# Generated deterministically by seda-macro-lef-normalizer-v1; recipe orfs-ng45-fakeram-metal3-coupledl2-pg-v1.
VERSION 5.8 ;
BUSBITCHARS "[]" ;
DIVIDERCHAR "/" ;

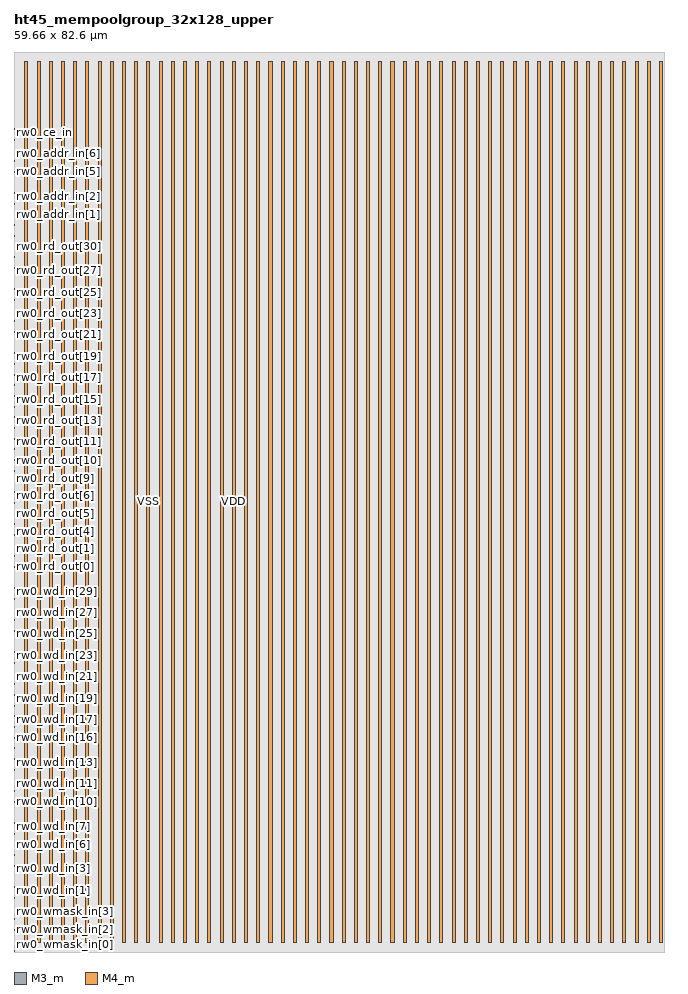
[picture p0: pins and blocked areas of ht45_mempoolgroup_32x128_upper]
MACRO ht45_mempoolgroup_32x128_upper
  FOREIGN ht45_mempoolgroup_32x128_upper 0 0 ;
  CLASS COVER ;
  ORIGIN 0 0 ;
  SIZE 59.66 BY 82.6 ;
  SYMMETRY X Y R90 ;
  PIN rw0_wmask_in[0]
    DIRECTION INPUT ;
    USE SIGNAL ;
    SHAPE ABUTMENT ;
    PORT
      LAYER M3_m ;
      RECT 0 0.035 0.07 0.105 ;
    END
  END rw0_wmask_in[0]
  PIN rw0_wmask_in[1]
    DIRECTION INPUT ;
    USE SIGNAL ;
    SHAPE ABUTMENT ;
    PORT
      LAYER M3_m ;
      RECT 0 1.015 0.07 1.085 ;
    END
  END rw0_wmask_in[1]
  PIN rw0_wmask_in[2]
    DIRECTION INPUT ;
    USE SIGNAL ;
    SHAPE ABUTMENT ;
    PORT
      LAYER M3_m ;
      RECT 0 1.995 0.07 2.065 ;
    END
  END rw0_wmask_in[2]
  PIN rw0_wmask_in[3]
    DIRECTION INPUT ;
    USE SIGNAL ;
    SHAPE ABUTMENT ;
    PORT
      LAYER M3_m ;
      RECT 0 2.975 0.07 3.045 ;
    END
  END rw0_wmask_in[3]
  PIN rw0_wd_in[0]
    DIRECTION INPUT ;
    USE SIGNAL ;
    SHAPE ABUTMENT ;
    PORT
      LAYER M3_m ;
      RECT 0 3.955 0.07 4.025 ;
    END
  END rw0_wd_in[0]
  PIN rw0_wd_in[1]
    DIRECTION INPUT ;
    USE SIGNAL ;
    SHAPE ABUTMENT ;
    PORT
      LAYER M3_m ;
      RECT 0 4.935 0.07 5.005 ;
    END
  END rw0_wd_in[1]
  PIN rw0_wd_in[2]
    DIRECTION INPUT ;
    USE SIGNAL ;
    SHAPE ABUTMENT ;
    PORT
      LAYER M3_m ;
      RECT 0 5.915 0.07 5.985 ;
    END
  END rw0_wd_in[2]
  PIN rw0_wd_in[3]
    DIRECTION INPUT ;
    USE SIGNAL ;
    SHAPE ABUTMENT ;
    PORT
      LAYER M3_m ;
      RECT 0 6.895 0.07 6.965 ;
    END
  END rw0_wd_in[3]
  PIN rw0_wd_in[4]
    DIRECTION INPUT ;
    USE SIGNAL ;
    SHAPE ABUTMENT ;
    PORT
      LAYER M3_m ;
      RECT 0 7.875 0.07 7.945 ;
    END
  END rw0_wd_in[4]
  PIN rw0_wd_in[5]
    DIRECTION INPUT ;
    USE SIGNAL ;
    SHAPE ABUTMENT ;
    PORT
      LAYER M3_m ;
      RECT 0 8.855 0.07 8.925 ;
    END
  END rw0_wd_in[5]
  PIN rw0_wd_in[6]
    DIRECTION INPUT ;
    USE SIGNAL ;
    SHAPE ABUTMENT ;
    PORT
      LAYER M3_m ;
      RECT 0 9.835 0.07 9.905 ;
    END
  END rw0_wd_in[6]
  PIN rw0_wd_in[7]
    DIRECTION INPUT ;
    USE SIGNAL ;
    SHAPE ABUTMENT ;
    PORT
      LAYER M3_m ;
      RECT 0 10.815 0.07 10.885 ;
    END
  END rw0_wd_in[7]
  PIN rw0_wd_in[8]
    DIRECTION INPUT ;
    USE SIGNAL ;
    SHAPE ABUTMENT ;
    PORT
      LAYER M3_m ;
      RECT 0 11.795 0.07 11.865 ;
    END
  END rw0_wd_in[8]
  PIN rw0_wd_in[9]
    DIRECTION INPUT ;
    USE SIGNAL ;
    SHAPE ABUTMENT ;
    PORT
      LAYER M3_m ;
      RECT 0 12.775 0.07 12.845 ;
    END
  END rw0_wd_in[9]
  PIN rw0_wd_in[10]
    DIRECTION INPUT ;
    USE SIGNAL ;
    SHAPE ABUTMENT ;
    PORT
      LAYER M3_m ;
      RECT 0 13.755 0.07 13.825 ;
    END
  END rw0_wd_in[10]
  PIN rw0_wd_in[11]
    DIRECTION INPUT ;
    USE SIGNAL ;
    SHAPE ABUTMENT ;
    PORT
      LAYER M3_m ;
      RECT 0 14.735 0.07 14.805 ;
    END
  END rw0_wd_in[11]
  PIN rw0_wd_in[12]
    DIRECTION INPUT ;
    USE SIGNAL ;
    SHAPE ABUTMENT ;
    PORT
      LAYER M3_m ;
      RECT 0 15.715 0.07 15.785 ;
    END
  END rw0_wd_in[12]
  PIN rw0_wd_in[13]
    DIRECTION INPUT ;
    USE SIGNAL ;
    SHAPE ABUTMENT ;
    PORT
      LAYER M3_m ;
      RECT 0 16.695 0.07 16.765 ;
    END
  END rw0_wd_in[13]
  PIN rw0_wd_in[14]
    DIRECTION INPUT ;
    USE SIGNAL ;
    SHAPE ABUTMENT ;
    PORT
      LAYER M3_m ;
      RECT 0 17.675 0.07 17.745 ;
    END
  END rw0_wd_in[14]
  PIN rw0_wd_in[15]
    DIRECTION INPUT ;
    USE SIGNAL ;
    SHAPE ABUTMENT ;
    PORT
      LAYER M3_m ;
      RECT 0 18.655 0.07 18.725 ;
    END
  END rw0_wd_in[15]
  PIN rw0_wd_in[16]
    DIRECTION INPUT ;
    USE SIGNAL ;
    SHAPE ABUTMENT ;
    PORT
      LAYER M3_m ;
      RECT 0 19.635 0.07 19.705 ;
    END
  END rw0_wd_in[16]
  PIN rw0_wd_in[17]
    DIRECTION INPUT ;
    USE SIGNAL ;
    SHAPE ABUTMENT ;
    PORT
      LAYER M3_m ;
      RECT 0 20.615 0.07 20.685 ;
    END
  END rw0_wd_in[17]
  PIN rw0_wd_in[18]
    DIRECTION INPUT ;
    USE SIGNAL ;
    SHAPE ABUTMENT ;
    PORT
      LAYER M3_m ;
      RECT 0 21.595 0.07 21.665 ;
    END
  END rw0_wd_in[18]
  PIN rw0_wd_in[19]
    DIRECTION INPUT ;
    USE SIGNAL ;
    SHAPE ABUTMENT ;
    PORT
      LAYER M3_m ;
      RECT 0 22.575 0.07 22.645 ;
    END
  END rw0_wd_in[19]
  PIN rw0_wd_in[20]
    DIRECTION INPUT ;
    USE SIGNAL ;
    SHAPE ABUTMENT ;
    PORT
      LAYER M3_m ;
      RECT 0 23.555 0.07 23.625 ;
    END
  END rw0_wd_in[20]
  PIN rw0_wd_in[21]
    DIRECTION INPUT ;
    USE SIGNAL ;
    SHAPE ABUTMENT ;
    PORT
      LAYER M3_m ;
      RECT 0 24.535 0.07 24.605 ;
    END
  END rw0_wd_in[21]
  PIN rw0_wd_in[22]
    DIRECTION INPUT ;
    USE SIGNAL ;
    SHAPE ABUTMENT ;
    PORT
      LAYER M3_m ;
      RECT 0 25.515 0.07 25.585 ;
    END
  END rw0_wd_in[22]
  PIN rw0_wd_in[23]
    DIRECTION INPUT ;
    USE SIGNAL ;
    SHAPE ABUTMENT ;
    PORT
      LAYER M3_m ;
      RECT 0 26.495 0.07 26.565 ;
    END
  END rw0_wd_in[23]
  PIN rw0_wd_in[24]
    DIRECTION INPUT ;
    USE SIGNAL ;
    SHAPE ABUTMENT ;
    PORT
      LAYER M3_m ;
      RECT 0 27.475 0.07 27.545 ;
    END
  END rw0_wd_in[24]
  PIN rw0_wd_in[25]
    DIRECTION INPUT ;
    USE SIGNAL ;
    SHAPE ABUTMENT ;
    PORT
      LAYER M3_m ;
      RECT 0 28.455 0.07 28.525 ;
    END
  END rw0_wd_in[25]
  PIN rw0_wd_in[26]
    DIRECTION INPUT ;
    USE SIGNAL ;
    SHAPE ABUTMENT ;
    PORT
      LAYER M3_m ;
      RECT 0 29.435 0.07 29.505 ;
    END
  END rw0_wd_in[26]
  PIN rw0_wd_in[27]
    DIRECTION INPUT ;
    USE SIGNAL ;
    SHAPE ABUTMENT ;
    PORT
      LAYER M3_m ;
      RECT 0 30.415 0.07 30.485 ;
    END
  END rw0_wd_in[27]
  PIN rw0_wd_in[28]
    DIRECTION INPUT ;
    USE SIGNAL ;
    SHAPE ABUTMENT ;
    PORT
      LAYER M3_m ;
      RECT 0 31.395 0.07 31.465 ;
    END
  END rw0_wd_in[28]
  PIN rw0_wd_in[29]
    DIRECTION INPUT ;
    USE SIGNAL ;
    SHAPE ABUTMENT ;
    PORT
      LAYER M3_m ;
      RECT 0 32.375 0.07 32.445 ;
    END
  END rw0_wd_in[29]
  PIN rw0_wd_in[30]
    DIRECTION INPUT ;
    USE SIGNAL ;
    SHAPE ABUTMENT ;
    PORT
      LAYER M3_m ;
      RECT 0 33.355 0.07 33.425 ;
    END
  END rw0_wd_in[30]
  PIN rw0_wd_in[31]
    DIRECTION INPUT ;
    USE SIGNAL ;
    SHAPE ABUTMENT ;
    PORT
      LAYER M3_m ;
      RECT 0 34.335 0.07 34.405 ;
    END
  END rw0_wd_in[31]
  PIN rw0_rd_out[0]
    DIRECTION OUTPUT ;
    USE SIGNAL ;
    SHAPE ABUTMENT ;
    PORT
      LAYER M3_m ;
      RECT 0 35.315 0.07 35.385 ;
    END
  END rw0_rd_out[0]
  PIN rw0_rd_out[1]
    DIRECTION OUTPUT ;
    USE SIGNAL ;
    SHAPE ABUTMENT ;
    PORT
      LAYER M3_m ;
      RECT 0 36.295 0.07 36.365 ;
    END
  END rw0_rd_out[1]
  PIN rw0_rd_out[2]
    DIRECTION OUTPUT ;
    USE SIGNAL ;
    SHAPE ABUTMENT ;
    PORT
      LAYER M3_m ;
      RECT 0 37.275 0.07 37.345 ;
    END
  END rw0_rd_out[2]
  PIN rw0_rd_out[3]
    DIRECTION OUTPUT ;
    USE SIGNAL ;
    SHAPE ABUTMENT ;
    PORT
      LAYER M3_m ;
      RECT 0 38.255 0.07 38.325 ;
    END
  END rw0_rd_out[3]
  PIN rw0_rd_out[4]
    DIRECTION OUTPUT ;
    USE SIGNAL ;
    SHAPE ABUTMENT ;
    PORT
      LAYER M3_m ;
      RECT 0 39.235 0.07 39.305 ;
    END
  END rw0_rd_out[4]
  PIN rw0_rd_out[5]
    DIRECTION OUTPUT ;
    USE SIGNAL ;
    SHAPE ABUTMENT ;
    PORT
      LAYER M3_m ;
      RECT 0 40.215 0.07 40.285 ;
    END
  END rw0_rd_out[5]
  PIN rw0_rd_out[6]
    DIRECTION OUTPUT ;
    USE SIGNAL ;
    SHAPE ABUTMENT ;
    PORT
      LAYER M3_m ;
      RECT 0 41.195 0.07 41.265 ;
    END
  END rw0_rd_out[6]
  PIN rw0_rd_out[7]
    DIRECTION OUTPUT ;
    USE SIGNAL ;
    SHAPE ABUTMENT ;
    PORT
      LAYER M3_m ;
      RECT 0 42.175 0.07 42.245 ;
    END
  END rw0_rd_out[7]
  PIN rw0_rd_out[8]
    DIRECTION OUTPUT ;
    USE SIGNAL ;
    SHAPE ABUTMENT ;
    PORT
      LAYER M3_m ;
      RECT 0 43.155 0.07 43.225 ;
    END
  END rw0_rd_out[8]
  PIN rw0_rd_out[9]
    DIRECTION OUTPUT ;
    USE SIGNAL ;
    SHAPE ABUTMENT ;
    PORT
      LAYER M3_m ;
      RECT 0 44.135 0.07 44.205 ;
    END
  END rw0_rd_out[9]
  PIN rw0_rd_out[10]
    DIRECTION OUTPUT ;
    USE SIGNAL ;
    SHAPE ABUTMENT ;
    PORT
      LAYER M3_m ;
      RECT 0 45.115 0.07 45.185 ;
    END
  END rw0_rd_out[10]
  PIN rw0_rd_out[11]
    DIRECTION OUTPUT ;
    USE SIGNAL ;
    SHAPE ABUTMENT ;
    PORT
      LAYER M3_m ;
      RECT 0 46.095 0.07 46.165 ;
    END
  END rw0_rd_out[11]
  PIN rw0_rd_out[12]
    DIRECTION OUTPUT ;
    USE SIGNAL ;
    SHAPE ABUTMENT ;
    PORT
      LAYER M3_m ;
      RECT 0 47.075 0.07 47.145 ;
    END
  END rw0_rd_out[12]
  PIN rw0_rd_out[13]
    DIRECTION OUTPUT ;
    USE SIGNAL ;
    SHAPE ABUTMENT ;
    PORT
      LAYER M3_m ;
      RECT 0 48.055 0.07 48.125 ;
    END
  END rw0_rd_out[13]
  PIN rw0_rd_out[14]
    DIRECTION OUTPUT ;
    USE SIGNAL ;
    SHAPE ABUTMENT ;
    PORT
      LAYER M3_m ;
      RECT 0 49.035 0.07 49.105 ;
    END
  END rw0_rd_out[14]
  PIN rw0_rd_out[15]
    DIRECTION OUTPUT ;
    USE SIGNAL ;
    SHAPE ABUTMENT ;
    PORT
      LAYER M3_m ;
      RECT 0 50.015 0.07 50.085 ;
    END
  END rw0_rd_out[15]
  PIN rw0_rd_out[16]
    DIRECTION OUTPUT ;
    USE SIGNAL ;
    SHAPE ABUTMENT ;
    PORT
      LAYER M3_m ;
      RECT 0 50.995 0.07 51.065 ;
    END
  END rw0_rd_out[16]
  PIN rw0_rd_out[17]
    DIRECTION OUTPUT ;
    USE SIGNAL ;
    SHAPE ABUTMENT ;
    PORT
      LAYER M3_m ;
      RECT 0 51.975 0.07 52.045 ;
    END
  END rw0_rd_out[17]
  PIN rw0_rd_out[18]
    DIRECTION OUTPUT ;
    USE SIGNAL ;
    SHAPE ABUTMENT ;
    PORT
      LAYER M3_m ;
      RECT 0 52.955 0.07 53.025 ;
    END
  END rw0_rd_out[18]
  PIN rw0_rd_out[19]
    DIRECTION OUTPUT ;
    USE SIGNAL ;
    SHAPE ABUTMENT ;
    PORT
      LAYER M3_m ;
      RECT 0 53.935 0.07 54.005 ;
    END
  END rw0_rd_out[19]
  PIN rw0_rd_out[20]
    DIRECTION OUTPUT ;
    USE SIGNAL ;
    SHAPE ABUTMENT ;
    PORT
      LAYER M3_m ;
      RECT 0 54.915 0.07 54.985 ;
    END
  END rw0_rd_out[20]
  PIN rw0_rd_out[21]
    DIRECTION OUTPUT ;
    USE SIGNAL ;
    SHAPE ABUTMENT ;
    PORT
      LAYER M3_m ;
      RECT 0 55.895 0.07 55.965 ;
    END
  END rw0_rd_out[21]
  PIN rw0_rd_out[22]
    DIRECTION OUTPUT ;
    USE SIGNAL ;
    SHAPE ABUTMENT ;
    PORT
      LAYER M3_m ;
      RECT 0 56.875 0.07 56.945 ;
    END
  END rw0_rd_out[22]
  PIN rw0_rd_out[23]
    DIRECTION OUTPUT ;
    USE SIGNAL ;
    SHAPE ABUTMENT ;
    PORT
      LAYER M3_m ;
      RECT 0 57.855 0.07 57.925 ;
    END
  END rw0_rd_out[23]
  PIN rw0_rd_out[24]
    DIRECTION OUTPUT ;
    USE SIGNAL ;
    SHAPE ABUTMENT ;
    PORT
      LAYER M3_m ;
      RECT 0 58.835 0.07 58.905 ;
    END
  END rw0_rd_out[24]
  PIN rw0_rd_out[25]
    DIRECTION OUTPUT ;
    USE SIGNAL ;
    SHAPE ABUTMENT ;
    PORT
      LAYER M3_m ;
      RECT 0 59.815 0.07 59.885 ;
    END
  END rw0_rd_out[25]
  PIN rw0_rd_out[26]
    DIRECTION OUTPUT ;
    USE SIGNAL ;
    SHAPE ABUTMENT ;
    PORT
      LAYER M3_m ;
      RECT 0 60.795 0.07 60.865 ;
    END
  END rw0_rd_out[26]
  PIN rw0_rd_out[27]
    DIRECTION OUTPUT ;
    USE SIGNAL ;
    SHAPE ABUTMENT ;
    PORT
      LAYER M3_m ;
      RECT 0 61.775 0.07 61.845 ;
    END
  END rw0_rd_out[27]
  PIN rw0_rd_out[28]
    DIRECTION OUTPUT ;
    USE SIGNAL ;
    SHAPE ABUTMENT ;
    PORT
      LAYER M3_m ;
      RECT 0 62.755 0.07 62.825 ;
    END
  END rw0_rd_out[28]
  PIN rw0_rd_out[29]
    DIRECTION OUTPUT ;
    USE SIGNAL ;
    SHAPE ABUTMENT ;
    PORT
      LAYER M3_m ;
      RECT 0 63.735 0.07 63.805 ;
    END
  END rw0_rd_out[29]
  PIN rw0_rd_out[30]
    DIRECTION OUTPUT ;
    USE SIGNAL ;
    SHAPE ABUTMENT ;
    PORT
      LAYER M3_m ;
      RECT 0 64.715 0.07 64.785 ;
    END
  END rw0_rd_out[30]
  PIN rw0_rd_out[31]
    DIRECTION OUTPUT ;
    USE SIGNAL ;
    SHAPE ABUTMENT ;
    PORT
      LAYER M3_m ;
      RECT 0 65.695 0.07 65.765 ;
    END
  END rw0_rd_out[31]
  PIN rw0_addr_in[0]
    DIRECTION INPUT ;
    USE SIGNAL ;
    SHAPE ABUTMENT ;
    PORT
      LAYER M3_m ;
      RECT 0 66.675 0.07 66.745 ;
    END
  END rw0_addr_in[0]
  PIN rw0_addr_in[1]
    DIRECTION INPUT ;
    USE SIGNAL ;
    SHAPE ABUTMENT ;
    PORT
      LAYER M3_m ;
      RECT 0 67.655 0.07 67.725 ;
    END
  END rw0_addr_in[1]
  PIN rw0_addr_in[2]
    DIRECTION INPUT ;
    USE SIGNAL ;
    SHAPE ABUTMENT ;
    PORT
      LAYER M3_m ;
      RECT 0 68.635 0.07 68.705 ;
    END
  END rw0_addr_in[2]
  PIN rw0_addr_in[3]
    DIRECTION INPUT ;
    USE SIGNAL ;
    SHAPE ABUTMENT ;
    PORT
      LAYER M3_m ;
      RECT 0 69.615 0.07 69.685 ;
    END
  END rw0_addr_in[3]
  PIN rw0_addr_in[4]
    DIRECTION INPUT ;
    USE SIGNAL ;
    SHAPE ABUTMENT ;
    PORT
      LAYER M3_m ;
      RECT 0 70.595 0.07 70.665 ;
    END
  END rw0_addr_in[4]
  PIN rw0_addr_in[5]
    DIRECTION INPUT ;
    USE SIGNAL ;
    SHAPE ABUTMENT ;
    PORT
      LAYER M3_m ;
      RECT 0 71.575 0.07 71.645 ;
    END
  END rw0_addr_in[5]
  PIN rw0_addr_in[6]
    DIRECTION INPUT ;
    USE SIGNAL ;
    SHAPE ABUTMENT ;
    PORT
      LAYER M3_m ;
      RECT 0 72.555 0.07 72.625 ;
    END
  END rw0_addr_in[6]
  PIN rw0_we_in
    DIRECTION INPUT ;
    USE SIGNAL ;
    SHAPE ABUTMENT ;
    PORT
      LAYER M3_m ;
      RECT 0 73.535 0.07 73.605 ;
    END
  END rw0_we_in
  PIN rw0_ce_in
    DIRECTION INPUT ;
    USE SIGNAL ;
    SHAPE ABUTMENT ;
    PORT
      LAYER M3_m ;
      RECT 0 74.515 0.07 74.585 ;
    END
  END rw0_ce_in
  PIN rw0_clk
    DIRECTION INPUT ;
    USE SIGNAL ;
    SHAPE ABUTMENT ;
    PORT
      LAYER M3_m ;
      RECT 0 75.495 0.07 75.565 ;
    END
  END rw0_clk
  PIN VSS
    DIRECTION INOUT ;
    USE GROUND ;
    PORT
      LAYER M4_m ;
      RECT 1 0.84 1.28 81.76 ;
      RECT 3.24 0.84 3.52 81.76 ;
      RECT 5.48 0.84 5.76 81.76 ;
      RECT 7.72 0.84 8 81.76 ;
      RECT 9.96 0.84 10.24 81.76 ;
      RECT 12.2 0.84 12.48 81.76 ;
      RECT 14.44 0.84 14.72 81.76 ;
      RECT 16.68 0.84 16.96 81.76 ;
      RECT 18.92 0.84 19.2 81.76 ;
      RECT 21.16 0.84 21.44 81.76 ;
      RECT 23.4 0.84 23.68 81.76 ;
      RECT 25.64 0.84 25.92 81.76 ;
      RECT 27.88 0.84 28.16 81.76 ;
      RECT 30.12 0.84 30.4 81.76 ;
      RECT 32.36 0.84 32.64 81.76 ;
      RECT 34.6 0.84 34.88 81.76 ;
      RECT 36.84 0.84 37.12 81.76 ;
      RECT 39.08 0.84 39.36 81.76 ;
      RECT 41.32 0.84 41.6 81.76 ;
      RECT 43.56 0.84 43.84 81.76 ;
      RECT 45.8 0.84 46.08 81.76 ;
      RECT 48.04 0.84 48.32 81.76 ;
      RECT 50.28 0.84 50.56 81.76 ;
      RECT 52.52 0.84 52.8 81.76 ;
      RECT 54.76 0.84 55.04 81.76 ;
      RECT 57 0.84 57.28 81.76 ;
      RECT 59.24 0.84 59.52 81.76 ;
    END
  END VSS
  PIN VDD
    DIRECTION INOUT ;
    USE POWER ;
    PORT
      LAYER M4_m ;
      RECT 2.12 0.84 2.4 81.76 ;
      RECT 4.36 0.84 4.64 81.76 ;
      RECT 6.6 0.84 6.88 81.76 ;
      RECT 8.84 0.84 9.12 81.76 ;
      RECT 11.08 0.84 11.36 81.76 ;
      RECT 13.32 0.84 13.6 81.76 ;
      RECT 15.56 0.84 15.84 81.76 ;
      RECT 17.8 0.84 18.08 81.76 ;
      RECT 20.04 0.84 20.32 81.76 ;
      RECT 22.28 0.84 22.56 81.76 ;
      RECT 24.52 0.84 24.8 81.76 ;
      RECT 26.76 0.84 27.04 81.76 ;
      RECT 29 0.84 29.28 81.76 ;
      RECT 31.24 0.84 31.52 81.76 ;
      RECT 33.48 0.84 33.76 81.76 ;
      RECT 35.72 0.84 36 81.76 ;
      RECT 37.96 0.84 38.24 81.76 ;
      RECT 40.2 0.84 40.48 81.76 ;
      RECT 42.44 0.84 42.72 81.76 ;
      RECT 44.68 0.84 44.96 81.76 ;
      RECT 46.92 0.84 47.2 81.76 ;
      RECT 49.16 0.84 49.44 81.76 ;
      RECT 51.4 0.84 51.68 81.76 ;
      RECT 53.64 0.84 53.92 81.76 ;
      RECT 55.88 0.84 56.16 81.76 ;
      RECT 58.12 0.84 58.4 81.76 ;
    END
  END VDD
  OBS
    LAYER M1_m ;
    RECT 0 0 59.66 82.6 ;
    LAYER M2_m ;
    RECT 0 0 59.66 82.6 ;
  END
END ht45_mempoolgroup_32x128_upper

END LIBRARY
